
# LEF generated by Coriolis2 DEF exporter.
# For design <fpga_export>.

VERSION 5.7 ;

BUSBITCHARS "()" ;
DIVIDERCHAR "." ;
MANUFACTURINGGRID 1 ;

UNITS
   DATABASE MICRONS 100 ;
END UNITS

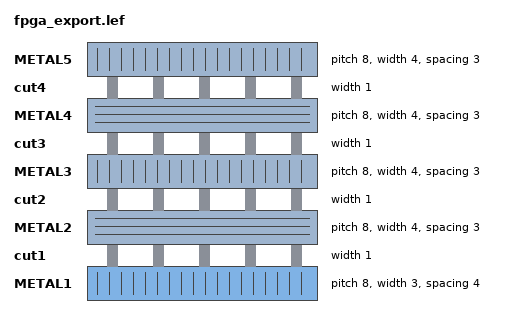
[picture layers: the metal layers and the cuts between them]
LAYER METAL1
   TYPE ROUTING ;
   DIRECTION VERTICAL ;
   WIDTH 3 ;
   OFFSET 4 ;
   PITCH 8 ;
   SPACING 4 ;
END METAL1

LAYER cut1
   TYPE CUT ;
   WIDTH 1 ;
END cut1

LAYER METAL2
   TYPE ROUTING ;
   DIRECTION HORIZONTAL ;
   WIDTH 4 ;
   OFFSET 0 ;
   PITCH 8 ;
   SPACING 3 ;
END METAL2

LAYER cut2
   TYPE CUT ;
   WIDTH 1 ;
END cut2

LAYER METAL3
   TYPE ROUTING ;
   DIRECTION VERTICAL ;
   WIDTH 4 ;
   OFFSET 4 ;
   PITCH 8 ;
   SPACING 3 ;
END METAL3

LAYER cut3
   TYPE CUT ;
   WIDTH 1 ;
END cut3

LAYER METAL4
   TYPE ROUTING ;
   DIRECTION HORIZONTAL ;
   WIDTH 4 ;
   OFFSET 0 ;
   PITCH 8 ;
   SPACING 3 ;
END METAL4

LAYER cut4
   TYPE CUT ;
   WIDTH 1 ;
END cut4

LAYER METAL5
   TYPE ROUTING ;
   DIRECTION VERTICAL ;
   WIDTH 4 ;
   OFFSET 4 ;
   PITCH 8 ;
   SPACING 3 ;
END METAL5

VIA VIA12 DEFAULT
   LAYER METAL1 ;
      RECT -1 -1 1 1 ;
   LAYER cut1 ;
      RECT -0.5 -0.5 0.5 0.5 ;
   LAYER METAL2 ;
      RECT -1.5 -1.5 1.5 1.5 ;
END VIA12

VIA VIA23 DEFAULT
   LAYER METAL2 ;
      RECT -1.5 -1.5 1.5 1.5 ;
   LAYER cut2 ;
      RECT -0.5 -0.5 0.5 0.5 ;
   LAYER METAL3 ;
      RECT -1.5 -1.5 1.5 1.5 ;
END VIA23

VIA VIA34 DEFAULT
   LAYER METAL3 ;
      RECT -1.5 -1.5 1.5 1.5 ;
   LAYER cut3 ;
      RECT -0.5 -0.5 0.5 0.5 ;
   LAYER METAL4 ;
      RECT -1.5 -1.5 1.5 1.5 ;
END VIA34

VIA VIA45 DEFAULT
   LAYER METAL4 ;
      RECT -1.5 -1.5 1.5 1.5 ;
   LAYER cut4 ;
      RECT -0.5 -0.5 0.5 0.5 ;
   LAYER METAL5 ;
      RECT -1.5 -1.5 1.5 1.5 ;
END VIA45

SITE core
   CLASS CORE ;
   SYMMETRY Y ;
   SIZE 8 BY 72 ;
END core

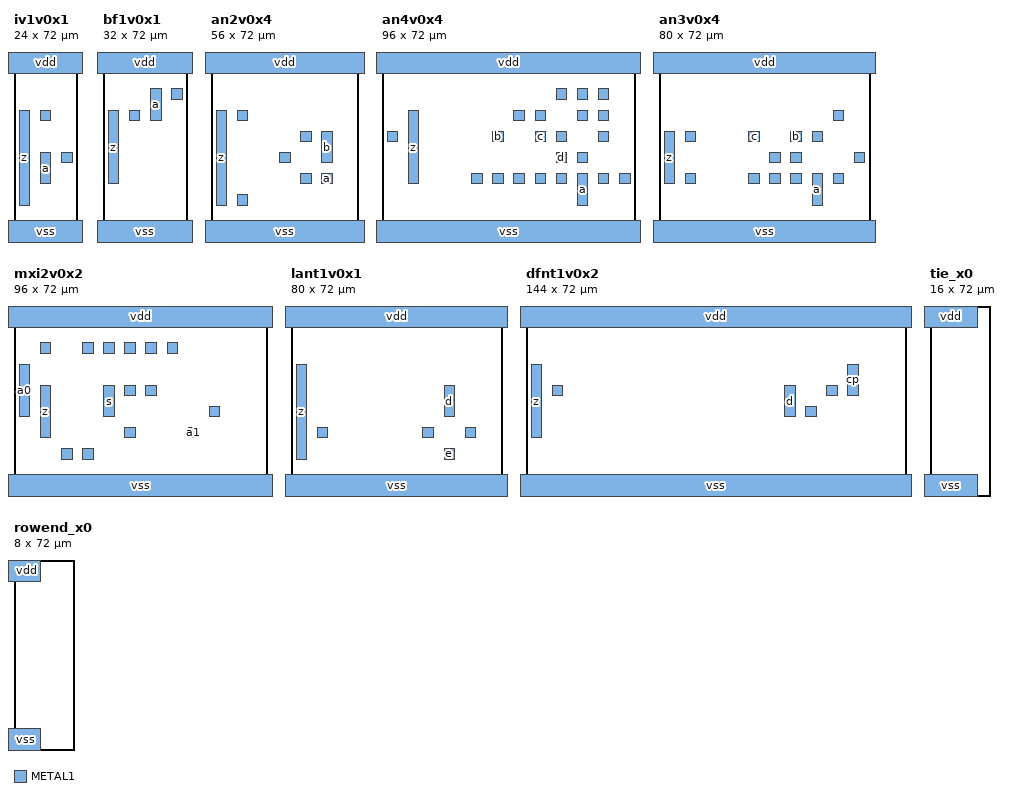
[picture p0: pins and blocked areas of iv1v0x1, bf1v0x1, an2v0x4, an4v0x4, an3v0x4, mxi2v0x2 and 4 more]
MACRO iv1v0x1
   CLASS CORE ;
   ORIGIN 0 0 ;
   SIZE 24 BY 72 ;
   SYMMETRY X Y ;
   SITE core ;
   PIN vdd
      DIRECTION INPUT ;
      SHAPE ABUTMENT ;
      USE POWER ;
      PORT 
         LAYER METAL1 ;
             RECT -2 64 26 72 ;
      END
   END vdd

   PIN vss
      DIRECTION INPUT ;
      SHAPE ABUTMENT ;
      USE GROUND ;
      PORT 
         LAYER METAL1 ;
             RECT -2 0 26 8 ;
      END
   END vss

   PIN a
      DIRECTION INPUT ;
      USE SIGNAL ;
      PORT 
         LAYER METAL1 ;
             RECT 18 30 22 34 ;
            RECT 10 22 14 34 ;
      END
   END a

   PIN z
      DIRECTION INPUT ;
      USE SIGNAL ;
      PORT 
         LAYER METAL1 ;
             RECT 10 46 14 50 ;
            RECT 2 14 6 50 ;
      END
   END z

END iv1v0x1

MACRO bf1v0x1
   CLASS CORE ;
   ORIGIN 0 0 ;
   SIZE 32 BY 72 ;
   SYMMETRY X Y ;
   SITE core ;
   PIN vdd
      DIRECTION INPUT ;
      SHAPE ABUTMENT ;
      USE POWER ;
      PORT 
         LAYER METAL1 ;
             RECT -2 64 34 72 ;
      END
   END vdd

   PIN vss
      DIRECTION INPUT ;
      SHAPE ABUTMENT ;
      USE GROUND ;
      PORT 
         LAYER METAL1 ;
             RECT -2 0 34 8 ;
      END
   END vss

   PIN a
      DIRECTION INPUT ;
      USE SIGNAL ;
      PORT 
         LAYER METAL1 ;
             RECT 26 54 30 58 ;
            RECT 18 46 22 58 ;
      END
   END a

   PIN z
      DIRECTION INPUT ;
      USE SIGNAL ;
      PORT 
         LAYER METAL1 ;
             RECT 2 22 6 50 ;
            RECT 10 46 14 50 ;
      END
   END z

END bf1v0x1

MACRO an2v0x4
   CLASS CORE ;
   ORIGIN 0 0 ;
   SIZE 56 BY 72 ;
   SYMMETRY X Y ;
   SITE core ;
   PIN b
      DIRECTION INPUT ;
      USE SIGNAL ;
      PORT 
         LAYER METAL1 ;
             RECT 42 30 46 42 ;
            RECT 34 38 38 42 ;
      END
   END b

   PIN vdd
      DIRECTION INPUT ;
      SHAPE ABUTMENT ;
      USE POWER ;
      PORT 
         LAYER METAL1 ;
             RECT -2 64 58 72 ;
      END
   END vdd

   PIN vss
      DIRECTION INPUT ;
      SHAPE ABUTMENT ;
      USE GROUND ;
      PORT 
         LAYER METAL1 ;
             RECT -2 0 58 8 ;
      END
   END vss

   PIN a
      DIRECTION INPUT ;
      USE SIGNAL ;
      PORT 
         LAYER METAL1 ;
             RECT 42 22 46 26 ;
            RECT 34 22 38 26 ;
            RECT 26 30 30 34 ;
      END
   END a

   PIN z
      DIRECTION INPUT ;
      USE SIGNAL ;
      PORT 
         LAYER METAL1 ;
             RECT 2 14 6 50 ;
            RECT 10 46 14 50 ;
            RECT 10 14 14 18 ;
      END
   END z

END an2v0x4

MACRO an4v0x4
   CLASS CORE ;
   ORIGIN 0 0 ;
   SIZE 96 BY 72 ;
   SYMMETRY X Y ;
   SITE core ;
   PIN d
      DIRECTION INPUT ;
      USE SIGNAL ;
      PORT 
         LAYER METAL1 ;
             RECT 66 30 70 34 ;
            RECT 74 30 78 34 ;
            RECT 82 38 86 42 ;
      END
   END d

   PIN c
      DIRECTION INPUT ;
      USE SIGNAL ;
      PORT 
         LAYER METAL1 ;
             RECT 58 38 62 42 ;
            RECT 66 38 70 42 ;
            RECT 74 46 78 50 ;
            RECT 82 46 86 50 ;
      END
   END c

   PIN b
      DIRECTION INPUT ;
      USE SIGNAL ;
      PORT 
         LAYER METAL1 ;
             RECT 42 38 46 42 ;
            RECT 50 46 54 50 ;
            RECT 58 46 62 50 ;
            RECT 66 54 70 58 ;
            RECT 74 54 78 58 ;
            RECT 82 54 86 58 ;
      END
   END b

   PIN vss
      DIRECTION INPUT ;
      SHAPE ABUTMENT ;
      USE GROUND ;
      PORT 
         LAYER METAL1 ;
             RECT -2 0 98 8 ;
      END
   END vss

   PIN vdd
      DIRECTION INPUT ;
      SHAPE ABUTMENT ;
      USE POWER ;
      PORT 
         LAYER METAL1 ;
             RECT -2 64 98 72 ;
      END
   END vdd

   PIN z
      DIRECTION INPUT ;
      USE SIGNAL ;
      PORT 
         LAYER METAL1 ;
             RECT 10 22 14 50 ;
            RECT 2 38 6 42 ;
      END
   END z

   PIN a
      DIRECTION INPUT ;
      USE SIGNAL ;
      PORT 
         LAYER METAL1 ;
             RECT 34 22 38 26 ;
            RECT 42 22 46 26 ;
            RECT 50 22 54 26 ;
            RECT 58 22 62 26 ;
            RECT 66 22 70 26 ;
            RECT 74 14 78 26 ;
            RECT 82 22 86 26 ;
            RECT 90 22 94 26 ;
      END
   END a

END an4v0x4

MACRO an3v0x4
   CLASS CORE ;
   ORIGIN 0 0 ;
   SIZE 80 BY 72 ;
   SYMMETRY X Y ;
   SITE core ;
   PIN c
      DIRECTION INPUT ;
      USE SIGNAL ;
      PORT 
         LAYER METAL1 ;
             RECT 34 38 38 42 ;
            RECT 42 30 46 34 ;
            RECT 50 30 54 34 ;
      END
   END c

   PIN b
      DIRECTION INPUT ;
      USE SIGNAL ;
      PORT 
         LAYER METAL1 ;
             RECT 50 38 54 42 ;
            RECT 58 38 62 42 ;
            RECT 66 46 70 50 ;
      END
   END b

   PIN vss
      DIRECTION INPUT ;
      SHAPE ABUTMENT ;
      USE GROUND ;
      PORT 
         LAYER METAL1 ;
             RECT -2 0 82 8 ;
      END
   END vss

   PIN vdd
      DIRECTION INPUT ;
      SHAPE ABUTMENT ;
      USE POWER ;
      PORT 
         LAYER METAL1 ;
             RECT -2 64 82 72 ;
      END
   END vdd

   PIN z
      DIRECTION INPUT ;
      USE SIGNAL ;
      PORT 
         LAYER METAL1 ;
             RECT 10 22 14 26 ;
            RECT 2 22 6 42 ;
            RECT 10 38 14 42 ;
      END
   END z

   PIN a
      DIRECTION INPUT ;
      USE SIGNAL ;
      PORT 
         LAYER METAL1 ;
             RECT 34 22 38 26 ;
            RECT 42 22 46 26 ;
            RECT 50 22 54 26 ;
            RECT 58 14 62 26 ;
            RECT 66 22 70 26 ;
            RECT 74 30 78 34 ;
      END
   END a

END an3v0x4

MACRO mxi2v0x2
   CLASS CORE ;
   ORIGIN 0 0 ;
   SIZE 96 BY 72 ;
   SYMMETRY X Y ;
   SITE core ;
   PIN a1
      DIRECTION INPUT ;
      USE SIGNAL ;
      PORT 
         LAYER METAL1 ;
             RECT 66 22 70 26 ;
            RECT 74 30 78 34 ;
            RECT 42 22 46 26 ;
      END
   END a1

   PIN a0
      DIRECTION INPUT ;
      USE SIGNAL ;
      PORT 
         LAYER METAL1 ;
             RECT 10 54 14 58 ;
            RECT 2 30 6 50 ;
      END
   END a0

   PIN s
      DIRECTION INPUT ;
      USE SIGNAL ;
      PORT 
         LAYER METAL1 ;
             RECT 50 38 54 42 ;
            RECT 42 38 46 42 ;
            RECT 34 30 38 42 ;
      END
   END s

   PIN vss
      DIRECTION INPUT ;
      SHAPE ABUTMENT ;
      USE GROUND ;
      PORT 
         LAYER METAL1 ;
             RECT -2 0 98 8 ;
      END
   END vss

   PIN vdd
      DIRECTION INPUT ;
      SHAPE ABUTMENT ;
      USE POWER ;
      PORT 
         LAYER METAL1 ;
             RECT -2 64 98 72 ;
      END
   END vdd

   PIN z
      DIRECTION INPUT ;
      USE SIGNAL ;
      PORT 
         LAYER METAL1 ;
             RECT 58 54 62 58 ;
            RECT 50 54 54 58 ;
            RECT 42 54 46 58 ;
            RECT 34 54 38 58 ;
            RECT 26 54 30 58 ;
            RECT 26 14 30 18 ;
            RECT 18 14 22 18 ;
            RECT 10 22 14 42 ;
      END
   END z

END mxi2v0x2

MACRO lant1v0x1
   CLASS CORE ;
   ORIGIN 0 0 ;
   SIZE 80 BY 72 ;
   SYMMETRY X Y ;
   SITE core ;
   PIN d
      DIRECTION INPUT ;
      USE SIGNAL ;
      PORT 
         LAYER METAL1 ;
             RECT 50 22 54 26 ;
            RECT 58 30 62 42 ;
      END
   END d

   PIN e
      DIRECTION INPUT ;
      USE SIGNAL ;
      PORT 
         LAYER METAL1 ;
             RECT 58 14 62 18 ;
            RECT 66 22 70 26 ;
      END
   END e

   PIN vss
      DIRECTION INPUT ;
      SHAPE ABUTMENT ;
      USE GROUND ;
      PORT 
         LAYER METAL1 ;
             RECT -2 0 82 8 ;
      END
   END vss

   PIN vdd
      DIRECTION INPUT ;
      SHAPE ABUTMENT ;
      USE POWER ;
      PORT 
         LAYER METAL1 ;
             RECT -2 64 82 72 ;
      END
   END vdd

   PIN z
      DIRECTION INPUT ;
      USE SIGNAL ;
      PORT 
         LAYER METAL1 ;
             RECT 10 22 14 26 ;
            RECT 2 14 6 50 ;
      END
   END z

END lant1v0x1

MACRO dfnt1v0x2
   CLASS CORE ;
   ORIGIN 0 0 ;
   SIZE 144 BY 72 ;
   SYMMETRY X Y ;
   SITE core ;
   PIN vdd
      DIRECTION INPUT ;
      SHAPE ABUTMENT ;
      USE POWER ;
      PORT 
         LAYER METAL1 ;
             RECT -2 64 146 72 ;
      END
   END vdd

   PIN vss
      DIRECTION INPUT ;
      SHAPE ABUTMENT ;
      USE GROUND ;
      PORT 
         LAYER METAL1 ;
             RECT -2 0 146 8 ;
      END
   END vss

   PIN z
      DIRECTION INPUT ;
      USE SIGNAL ;
      PORT 
         LAYER METAL1 ;
             RECT 2 22 6 50 ;
            RECT 10 38 14 42 ;
      END
   END z

   PIN d
      DIRECTION INPUT ;
      USE SIGNAL ;
      PORT 
         LAYER METAL1 ;
             RECT 98 30 102 42 ;
            RECT 106 30 110 34 ;
      END
   END d

   PIN cp
      DIRECTION INPUT ;
      USE SIGNAL ;
      PORT 
         LAYER METAL1 ;
             RECT 114 38 118 42 ;
            RECT 122 38 126 50 ;
      END
   END cp

END dfnt1v0x2

MACRO tie_x0
   CLASS CORE SPACER ;
   ORIGIN 0 0 ;
   SIZE 16 BY 72 ;
   SYMMETRY X Y ;
   SITE core ;
   PIN vss
      DIRECTION INPUT ;
      SHAPE ABUTMENT ;
      USE GROUND ;
      PORT 
         LAYER METAL1 ;
             RECT -2 0 18 8 ;
      END
   END vss

   PIN vdd
      DIRECTION INPUT ;
      SHAPE ABUTMENT ;
      USE POWER ;
      PORT 
         LAYER METAL1 ;
             RECT -2 64 18 72 ;
      END
   END vdd

END tie_x0

MACRO rowend_x0
   CLASS CORE SPACER ;
   ORIGIN 0 0 ;
   SIZE 8 BY 72 ;
   SYMMETRY X Y ;
   SITE core ;
   PIN vss
      DIRECTION INPUT ;
      SHAPE ABUTMENT ;
      USE GROUND ;
      PORT 
         LAYER METAL1 ;
             RECT -2 0 10 8 ;
      END
   END vss

   PIN vdd
      DIRECTION INPUT ;
      SHAPE ABUTMENT ;
      USE POWER ;
      PORT 
         LAYER METAL1 ;
             RECT -2 64 10 72 ;
      END
   END vdd

END rowend_x0

END LIBRARY
